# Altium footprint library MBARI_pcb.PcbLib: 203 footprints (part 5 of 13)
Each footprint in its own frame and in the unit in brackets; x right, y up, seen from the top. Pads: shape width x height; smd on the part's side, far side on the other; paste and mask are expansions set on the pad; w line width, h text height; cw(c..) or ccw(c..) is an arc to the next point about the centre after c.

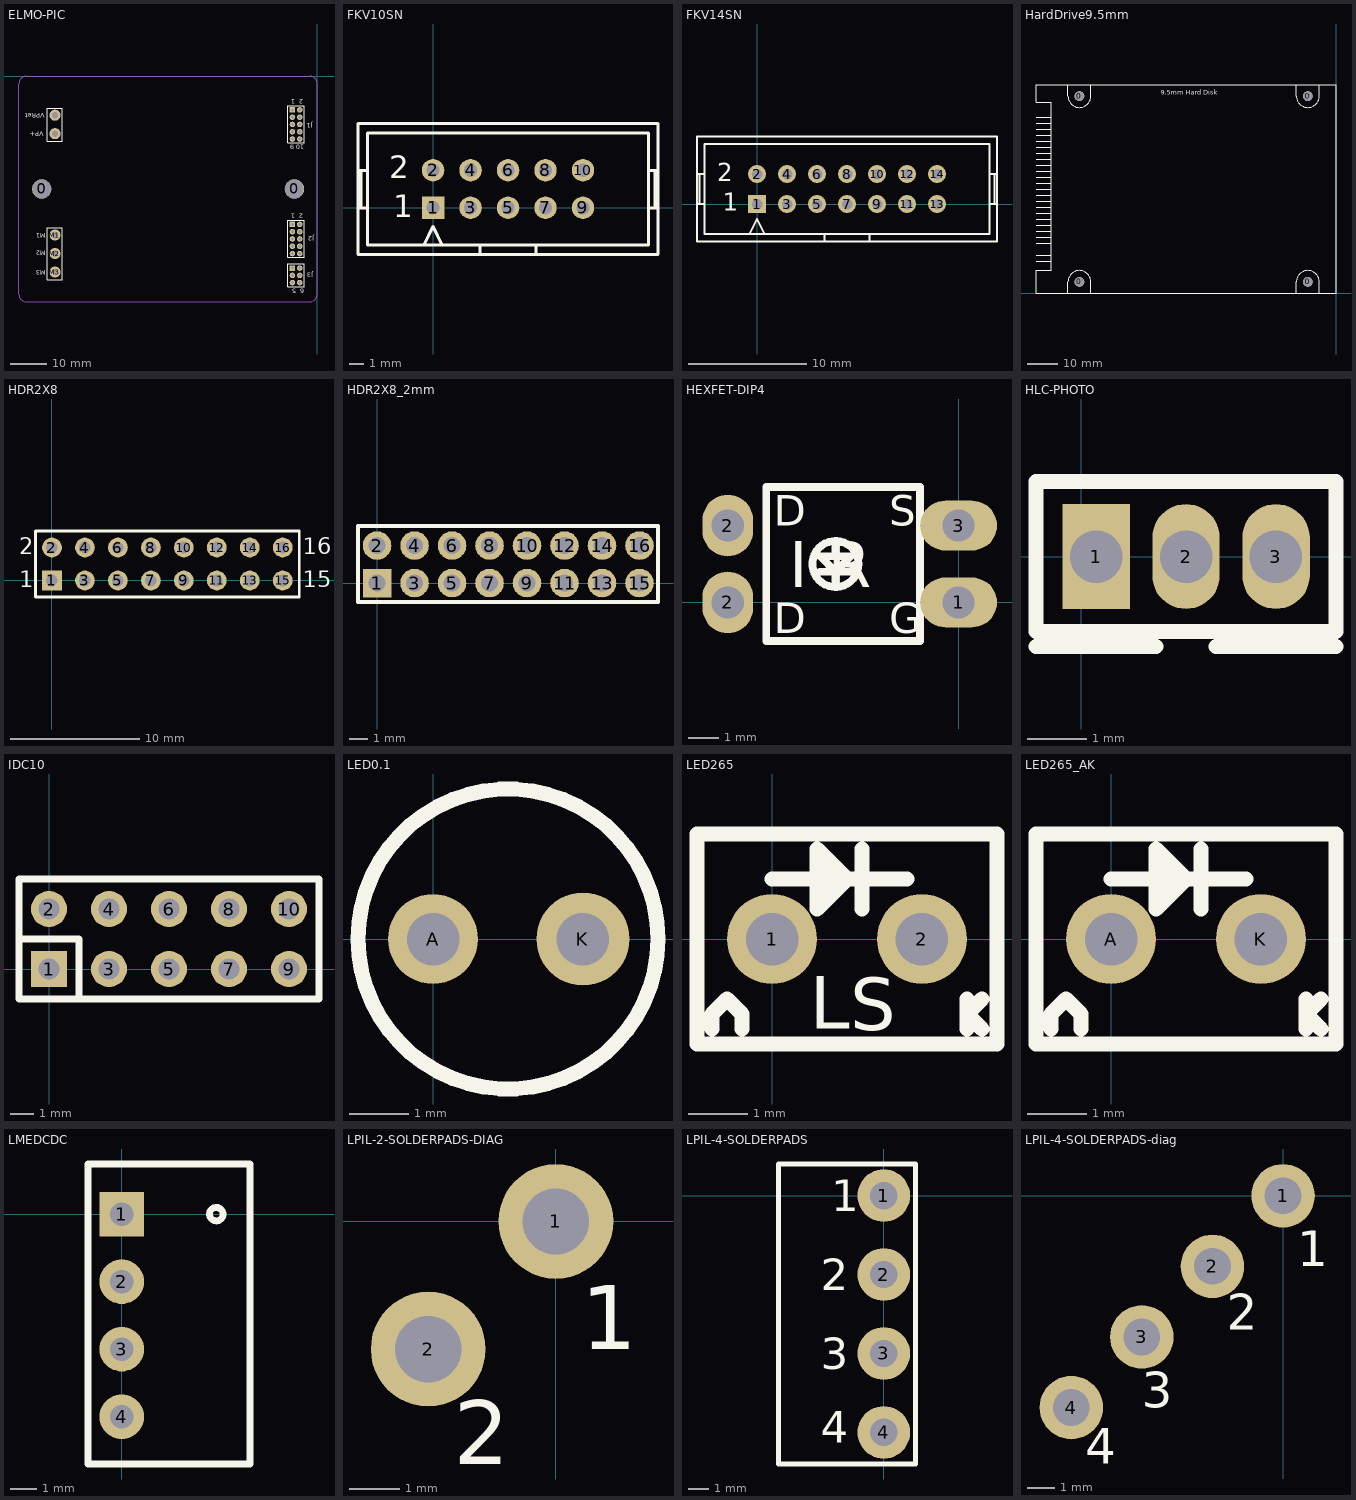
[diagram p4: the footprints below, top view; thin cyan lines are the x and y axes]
## ELMO-PIC [mil]
pads (33):
  round 210 hole 201: 0(-2982.28,-1220.47) 0(-246.06,-1220.47)
  rect 60x60 hole 35: J1.1(-267.32,-364.17) J2.1(-267.32,-1604.33) J3.1(-267.32,-2076.77)
  round 60 hole 35: J1.2(-188.58,-364.17) J1.3(-267.32,-442.91) J1.4(-188.58,-442.91) J1.5(-267.32,-521.65) J1.6(-188.58,-521.65) J1.7(-267.32,-600.39) J1.8(-188.58,-600.39) J1.9(-267.32,-679.13) J1.10(-188.58,-679.13) J2.2(-188.58,-1604.33) J2.3(-267.32,-1683.07) J2.4(-188.58,-1683.07) J2.5(-267.32,-1761.81) J2.6(-188.58,-1761.81) J2.7(-267.32,-1840.55) J2.8(-188.58,-1840.55) J2.9(-267.32,-1919.29) J2.10(-188.58,-1919.29) J3.2(-188.58,-2076.77) J3.3(-267.32,-2155.51) J3.4(-188.58,-2155.51) J3.5(-267.32,-2234.25) J3.6(-188.58,-2234.25)
  round 120 hole 70: M1(-2838.58,-1719.29) M2(-2838.58,-1919.29) M3(-2838.58,-2119.29) VP+(-2838.58,-621.65) VPRet(-2838.58,-421.65)
TopOverlay:
  lines w10: -145.67,-2031.5 -318.9,-2031.5 -318.9,-2279.53 -141.73,-2279.53 -141.73,-2031.5 ; -145.67,-1559.06 -318.9,-1559.06 -318.9,-1960.63 -141.73,-1960.63 -141.73,-1559.06 ; -145.67,-318.9 -318.9,-318.9 -318.9,-720.47 -141.73,-720.47 -141.73,-318.9 ; -2921.26,-2200.79 -2921.26,-1641.73 -2759.84,-1641.73 -2759.84,-2200.79 -2921.26,-2200.79 ; -2921.26,-702.36 -2921.26,-344.09 -2759.84,-344.09 -2759.84,-702.36 -2921.26,-702.36
  text "M3" at -2940,-2100 h50
  text "M2" at -2940,-1890 h50
  text "M1" at -2940,-1700 h50
  text "VPRet" at -2950,-400 h50
  text "VP+" at -2960,-600 h50
  text "10 9" at -140,-740 h50
  text "6  5" at -140,-2300 h50
  text "2  1" at -150,-250 h50
  text "2  1" at -150,-1490 h50
  text "J1" at -50,-510 h50
  text "J2" at -30,-1730 h50
  text "J3" at -40,-2130 h50
Mechanical1:
  lines w10: -3228.35,-2362.2 ccw(c-3149.61,-2362.2) -3149.61,-2440.94 -78.74,-2440.94 ccw(c-78.74,-2362.2) 0,-2362.2 0,-78.74 ccw(c-78.74,-78.74) -78.74,0 -3149.61,0 ccw(c-3149.61,-78.74) -3228.35,-78.74 -3228.35,-2362.2

## FKV10SN [mil]
pads (10):
  rect 60x60 hole 35: 1(0,0)
  round 60 hole 35: 2(0,100) 3(100,0) 4(100,100) 5(200,0) 6(200,100) 7(300,0) 8(300,100) 9(400,0) 10(400,100)
TopOverlay:
  lines w8: -200,0 -175,0 ; -200,100 -175,100 ; -191.67,0 -191.67,100 ; -25,-100 0,-50 25,-100 ; 125,-125 125,-100 ; 275,-125 275,-100 ; 575,0 600,0 ; 575,100 600,100 ; 591.67,0 591.67,100 ; 125,-100 275,-100 ; 125,-100 -175,-100 -175,200 575,200 575,-100 275,-100 ; -200,-125 600,-125 600,225 -200,225 -200,-125
  text "1" at -106,-26 h60
  text "2" at -117,79 h60

## FKV14SN [mil]
pads (14):
  rect 60x60 hole 35: 1(0,0)
  round 60 hole 35: 2(0,100) 3(100,0) 4(100,100) 5(200,0) 6(200,100) 7(300,0) 8(300,100) 9(400,0) 10(400,100) 11(500,0) 12(500,100) 13(600,0) 14(600,100)
TopOverlay:
  lines w8: -200,0 -175,0 ; -200,100 -175,100 ; -191.67,0 -191.67,100 ; -25,-100 0,-50 25,-100 ; 225,-125 225,-100 ; 375,-125 375,-100 ; 775,0 800,0 ; 775,100 800,100 ; 791.67,0 791.67,100 ; 225,-100 375,-100 ; 225,-100 -175,-100 -175,200 775,200 775,-100 375,-100 ; -200,-125 800,-125 800,225 -200,225 -200,-125
  text "2" at -132,76 h60
  text "1" at -115,-23 h60

## HardDrive9.5mm [mil] "Laptop Hard Drive"
height 375
pads (4):
  round 130 hole 125: 0(-3370,150) 0(-3370,2590) 0(-370,150) 0(-370,2590)
TopOverlay:
  lines w7: -3940,1365.12 -3740,1365.12
  lines w10: -3940,420.24 -3740,420.24 ; -3940,498.98 -3740,498.98 ; -3940,656.46 -3740,656.46 ; -3940,735.2 -3740,735.2 ; -3940,813.94 -3740,813.94 ; -3940,892.68 -3740,892.68 ; -3940,971.42 -3740,971.42 ; -3940,1050.16 -3740,1050.16 ; -3940,1128.9 -3740,1128.9 ; -3940,1207.64 -3740,1207.64 ; -3940,1286.38 -3740,1286.38 ; -3940,1443.86 -3740,1443.86 ; -3940,1522.6 -3740,1522.6 ; -3940,1601.34 -3740,1601.34 ; -3940,1680.08 -3740,1680.08 ; -3940,1758.82 -3740,1758.82 ; -3940,1837.56 -3740,1837.56 ; -3940,1916.3 -3740,1916.3 ; -3940,1995.04 -3740,1995.04 ; -3940,2073.78 -3740,2073.78 ; -3940,2152.52 -3740,2152.52 ; -3940,2231.26 -3740,2231.26 ; -3940,2310 -3740,2310 ; -3520,0 -3520,150 cw(c-3370,150) -3220,150 -3220,0 ; -3520,2740 -3520,2590 ccw(c-3370,2590) -3220,2590 -3220,2740 ; -520,0 -520,150 cw(c-370,150) -220,150 -220,0 ; -520,2740 -520,2590 ccw(c-370,2590) -220,2590 -220,2740 ; -3940,0 -3940,300 -3740,300 -3740,2510 -3940,2510 -3940,2740 0,2740 0,0 -3940,0
  text "9.5mm Hard Disk" at -2300,2610 h60

## HDR2X8 [mil]
pads (16):
  rect 60x60 hole 35: 1(0,-0.39)
  round 60 hole 35: 2(0,99.61) 3(100,-0.39) 4(100,99.61) 5(200,-0.39) 6(200,99.61) 7(300,-0.39) 8(300,99.61) 9(400,-0.39) 10(400,99.61) 11(500,-0.39) 12(500,99.61) 13(600,-0.39) 14(600,99.61) 15(700,-0.39) 16(700,99.61)
TopOverlay:
  lines w8: -50,-50.39 -50,149.61 750,149.61 750,-50.39 -50,-50.39
  text "2" at -100,79.61 h50
  text "1" at -100,-20.39 h50
  text "15" at 760,-20.39 h50
  text "16" at 760,79.61 h50

## HDR2X8_2mm [mil]
pads (16):
  rect 60x60 hole 35: 1(0,0)
  round 60 hole 35: 2(0,78.74) 3(78.74,0) 4(78.74,78.74) 5(157.48,0) 6(157.48,78.74) 7(236.22,0) 8(236.22,78.74) 9(314.96,0) 10(314.96,78.74) 11(393.7,0) 12(393.7,78.74) 13(472.44,0) 14(472.44,78.74) 15(551.18,0) 16(551.18,78.74)
TopOverlay:
  lines w8: -40,-40 -40,120 590,120 590,-40 -40,-40

## HEXFET-DIP4 [mil]
pads (4):
  oval 100x65 hole 42: 1(0,0) 3(0,100)
  oval 66x80 hole 42: 2(-300,0) 2(-300,100)
TopOverlay:
  circle w10: c-160,50 r30
  lines w10: -180,40 -140,40 ; -160,20 -160,40 ; -160,80 -160,60 ; -160,40 -180,60 -160,60 ; -160,40 -140,60 -160,60 ; -250,-50 -50,-50 -50,150 -250,150 -250,-50
  text "I R" at -220,20 h60
  text "S" at -90,100 h40
  text "G" at -90,-40 h40
  text "D" at -240,100 h40
  text "D" at -240,-40 h40

## HLC-PHOTO [mil]
pads (3):
  rect 45x70 hole 35: 1(10,0)
  oval 45x70 hole 35: 2(70,0) 3(130,0)
TopOverlay:
  lines w10: -30,-60 50,-60 ; 90,-60 170,-60 ; -30,-50 170,-50 170,50 -30,50 -30,-50

## IDC10 [mil]
pads (10):
  rect 60x60 hole 35: 1(0,0)
  round 60 hole 35: 2(0,100) 3(100,0) 4(100,100) 5(200,0) 6(200,100) 7(300,0) 8(300,100) 9(400,0) 10(400,100)
TopOverlay:
  lines w12: -50,50 50,50 50,-50 ; -50,-50 -50,150 450,150 450,-50 -50,-50

## LED0.1 [mil]
pads (2):
  round 60 hole 35: A(0,0)
  round 62 hole 35: K(100,0)
TopOverlay:
  circle w10: c50,0 r100

## LED265 [mil]
pads (2):
  round 60 hole 35: 1(0,0) 2(100,0)
TopOverlay:
  lines w10: -40,-60 -40,-50 -30,-40 -20,-50 -20,-60 ; 0,40 30,40 ; 36.22,26.22 36.22,53.78 ; 60,20 60,40 60,60 ; 90,40 30,40 ; 130,-40 130,-60 130,-50 ; 140,-60 130,-50 ; 30,40 30,60 ; 30,60 50,40 30,20 30,60 ; 130,-50 140,-40 130,-50 ; -50,-70 150,-70 150,70 -50,70 -50,-70
  text "S" at 52,-61 h35
  text "L" at 25,-60 h35

## LED265_AK [mil]
pads (2):
  round 60 hole 35: A(0,0) K(100,0)
TopOverlay:
  lines w10: -40,-60 -40,-50 -30,-40 -20,-50 -20,-60 ; 0,40 30,40 ; 36.22,26.22 36.22,53.78 ; 60,20 60,40 60,60 ; 90,40 30,40 ; 130,-40 130,-60 130,-50 ; 140,-60 130,-50 ; 30,40 30,60 ; 30,60 50,40 30,20 30,60 ; 130,-50 140,-40 130,-50 ; -50,-70 150,-70 150,70 -50,70 -50,-70

## LMEDCDC [mil] "C&D Tech DCDC LME"
height 39
pads (4):
  rect 66x66 hole 35: 1(0,0)
  round 66 hole 35: 2(0,-100) 3(0,-200) 4(0,-300)
TopOverlay:
  circle w10: c140,0 r10
  lines w10: -50,-370 -50,74.25 190,74.25 190,-370 -50,-370

## LPIL-2-SOLDERPADS-DIAG [mil]
pads (2):
  round 90 hole 52: 1(0,0) 2(-100,-100)
TopOverlay:
  text "2" at -80,-190 h50
  text "1" at 20,-100 h50

## LPIL-4-SOLDERPADS [mil]
pads (4):
  round 100 hole 52: 1(0,0) 2(0,-150) 3(0,-300) 4(0,-450)
TopOverlay:
  lines w10: -200,-510 -200,60 60,60 60,-510 -200,-510
  text "4" at -120,-470 h60
  text "3" at -120,-330 h60
  text "2" at -120,-180 h60
  text "1" at -100,-30 h60

## LPIL-4-SOLDERPADS-diag [mil]
pads (4):
  round 90 hole 52: 1(0,0) 2(-100,-100) 3(-200,-200) 4(-300,-300)
TopOverlay:
  text "1" at 20,-100 h50
  text "2" at -80,-190 h50
  text "3" at -200,-300 h50
  text "4" at -280,-380 h50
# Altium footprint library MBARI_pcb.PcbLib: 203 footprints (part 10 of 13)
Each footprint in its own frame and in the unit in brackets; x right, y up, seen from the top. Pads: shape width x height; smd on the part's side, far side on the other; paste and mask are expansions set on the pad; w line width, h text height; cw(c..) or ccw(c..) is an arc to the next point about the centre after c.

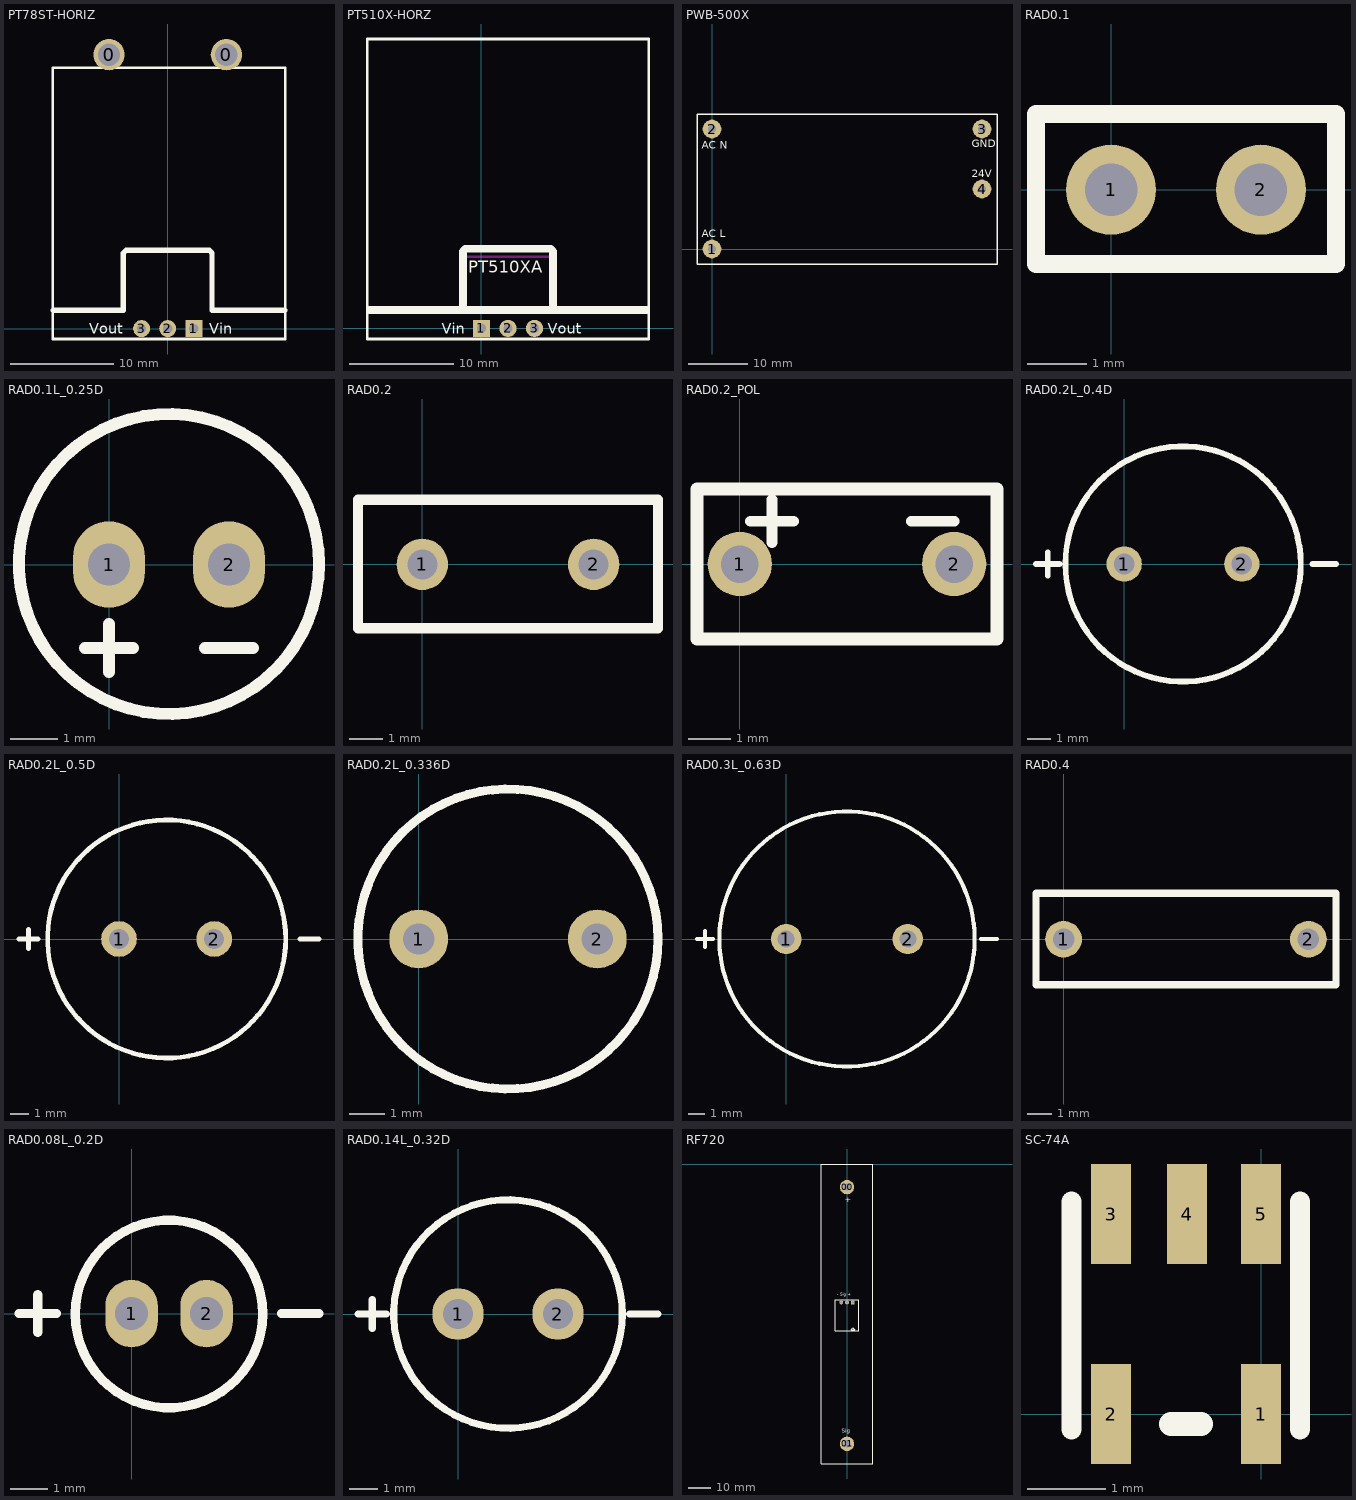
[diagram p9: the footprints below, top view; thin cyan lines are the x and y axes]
## PT78ST-HORIZ [mil]
pads (5):
  round 120 hole 86: 0(-225,1050) 0(225,1050)
  rect 65x65 hole 35: 1(100,0)
  round 65 hole 35: 2(0,0) 3(-100,0)
TopOverlay:
  lines w10: -440,-40 -440,1000 450,1000 450,-40 -150,-40 -440,-40
  lines w20: -440,70 -170,70 -170,290 -160,300 160,300 170,290 170,70 450,70
  text "Vin" at 160,-20 h40
  text "Vout" at -300,-20 h40

## PT510X-HORZ [mil]
pads (3):
  rect 65x65 hole 35: 1(0,0)
  round 65 hole 35: 2(100,0) 3(200,0)
TopOverlay:
  lines w10: -430,-40 -430,1090 630,1090 630,-40 -50,-40 -430,-40
  lines w30: -420,70 620,70 ; -70,70 -70,290 -60,300 260,300 270,290 270,70
  text "PT510XA" at -50,210 h45
  text "Vin" at -150,-20 h40
  text "Vout" at 250,-20 h40
KeepOutLayer:
  lines w10: -70,70 -70,270 270,270 270,70 -70,70

## PWB-500X [mil]
pads (4):
  round 125 hole 52: 1(0,0) 2(0,800) 3(1800,800) 4(1800,400)
TopOverlay:
  lines w10: -100,-100 -100,900 1900,900 1900,-100 -100,-100
  text "AC L" at -70,80 h50
  text "24V" at 1730,480 h50
  text "AC N" at -70,670 h50
  text "GND" at 1730,680 h50

## RAD0.1 [mil]
pads (2):
  round 60 hole 35: 1(0,0) 2(100,0)
TopOverlay:
  lines w12: -50,-49.51 -50,50.49 150,50.49 150,-49.51 -50,-49.51

## RAD0.1L_0.25D [mil]
pads (2):
  oval 60x72 hole 35: 1(0,0) 2(100,0)
TopOverlay:
  circle w10: c50,0.45 r125
  lines w10: -20,-69.55 20,-69.55 ; 0,-89.55 0,-49.55 ; 80,-69.55 120,-69.55

## RAD0.2 [mil]
pads (2):
  round 60 hole 35: 1(0,0) 2(200,0)
TopOverlay:
  lines w12: -75,-74.59 -75,75.41 275,75.41 275,-74.59 -75,-74.59

## RAD0.2_POL [mil] "Polarized Cap"
pads (2):
  round 60 hole 35: 1(0,0) 2(200,0)
TopOverlay:
  lines w10: 10,40 50,40 ; 30,20 30,60 ; 160,40 200,40
  lines w12: -40,-70 -40,70 240,70 240,-70 -40,-70

## RAD0.2L_0.4D [mil]
pads (2):
  round 60 hole 35: 1(0,0) 2(200,0)
TopOverlay:
  circle w10: c100,0 r200
  lines w10: -150,0 -110,0 ; -130,-20 -130,20 ; 320,0 360,0

## RAD0.2L_0.5D [mil]
pads (2):
  round 75 hole 42: 1(0,0) 2(200,0)
TopOverlay:
  circle w10: c100,0 r250
  lines w10: -210,0 -170,0 ; -190,-20 -190,20 ; 380,0 420,0

## RAD0.2L_0.336D [mil]
pads (2):
  round 66 hole 35: 1(0,0) 2(200,0)
TopOverlay:
  circle w10: c100,0 r168

## RAD0.3L_0.63D [mil]
pads (2):
  round 75 hole 42: 1(0,0) 2(300,0)
TopOverlay:
  circle w10: c150,0 r315
  lines w10: -220,0 -180,0 ; -200,-20 -200,20 ; 480,0 520,0

## RAD0.4 [mil]
pads (2):
  round 60 hole 35: 1(0,0) 2(400,0)
TopOverlay:
  lines w12: -45,-74.59 445,-74.59 445,75.41 -45,75.41 -45,-74.59

## RAD0.08L_0.2D [mil]
pads (2):
  oval 56x72 hole 35: 1(0,0) 2(80,0)
TopOverlay:
  circle w10: c40,-0.47 r100
  lines w10: -120,0 -80,0 ; -100,-20 -100,20 ; 160,0 200,0

## RAD0.14L_0.32D [mil]
pads (2):
  round 72 hole 42: 1(0,0) 2(140,0)
TopOverlay:
  circle w10: c70,0 r160
  lines w10: -140,0 -100,0 ; -120,-20 -120,20 ; 240,0 280,0

## RF720 [mil]
pads (5):
  round 250 hole 125: 00(0,-400) 01(0,-4850)
  rect 66x66 hole 42: 1(100,-2400)
  round 66 hole 42: 2(0,-2400) 3(-100,-2400)
TopOverlay:
  lines w10: -450,-5200 -450,-700 -450,0 450,0 450,-5200 -450,-5200 ; -200,-2890 -200,-2350 200,-2350 200,-2890 -200,-2890 ; 71.71,-2871.71 131.71,-2871.71 101.71,-2841.71 71.71,-2871.71
  text "- Sig +" at -170,-2280 h50
  text "+" at -40,-660 h100
  text "Sig" at -90,-4660 h70

## SC-74A [mil] "Mini5 - G1 Panasonic"
height 43.31
pads (5):
  rect 20x50 smd: 1(0,0) 2(-75,0) 3(-75,100) 4(-37,100) 5(0,100)
TopOverlay:
  lines w10: -94.69,-7.87 -94.69,106.3 ; 19.49,-7.87 19.49,106.3
  lines w12: -45,-5 -30,-5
